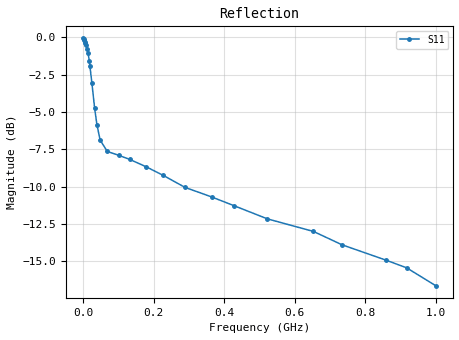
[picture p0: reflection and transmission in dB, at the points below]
! HEWLETT PACKARD,8753C,0,4.13
! 22 May 2016  21:51:27
! frequency  re(S11)  im(S11)
# Hz  S RI R 50
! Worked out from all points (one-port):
!   1601 points, 300 kHz to 1 GHz, reference 50 ohm
!   lowest |S11| = -16.6 dB at 1 GHz (marker M1), VSWR 1.35, Z = 54 + j15 ohm
!   |S11| at or under -10 dB: 284.9 MHz to end of sweep
!   S11 on the Smith chart (normalised r, x): 300 kHz: open; 18.88 MHz: 1.16, -2.92; 101.6 MHz: 1.37, -0.96; 426.7 MHz: 0.63, -0.25; 1 GHz: 1.08, +0.30
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300000  0.9927 -0.0179
831156  0.9859 -0.0361
2291092  0.9738 -0.0808
3862138  0.9607 -0.1262
6315422  0.9382 -0.1967
8691919  0.904 -0.2609
1.131382e7  0.8564 -0.328
1.406975e7  0.7961 -0.3834
1.740854e7  0.7115 -0.4311
1.887952e7  0.6725 -0.4429
2.445021e7  0.5412 -0.4529
3.247755e7  0.4135 -0.4044
3.898058e7  0.3627 -0.3581
4.79868e7  0.3307 -0.3098
6.843021e7  0.3105 -0.2753
1.016221e8  0.2747 -0.2943
1.322763e8  0.2186 -0.3232
1.793038e8  0.1244 -0.3468
2.275484e8  0.0356 -0.343
2.887745e8  -0.0622 -0.3084
3.646208e8  -0.1522 -0.2494
4.266748e8  -0.2006 -0.1859
5.225996e8  -0.2352 -0.0746
6.532023e8  -0.216 0.0592
7.339888e8  -0.1612 0.1219
8.589058e8  -0.0665 0.1667
9.174203e8  -0.00998 0.1689
1e9  0.058 0.1355
